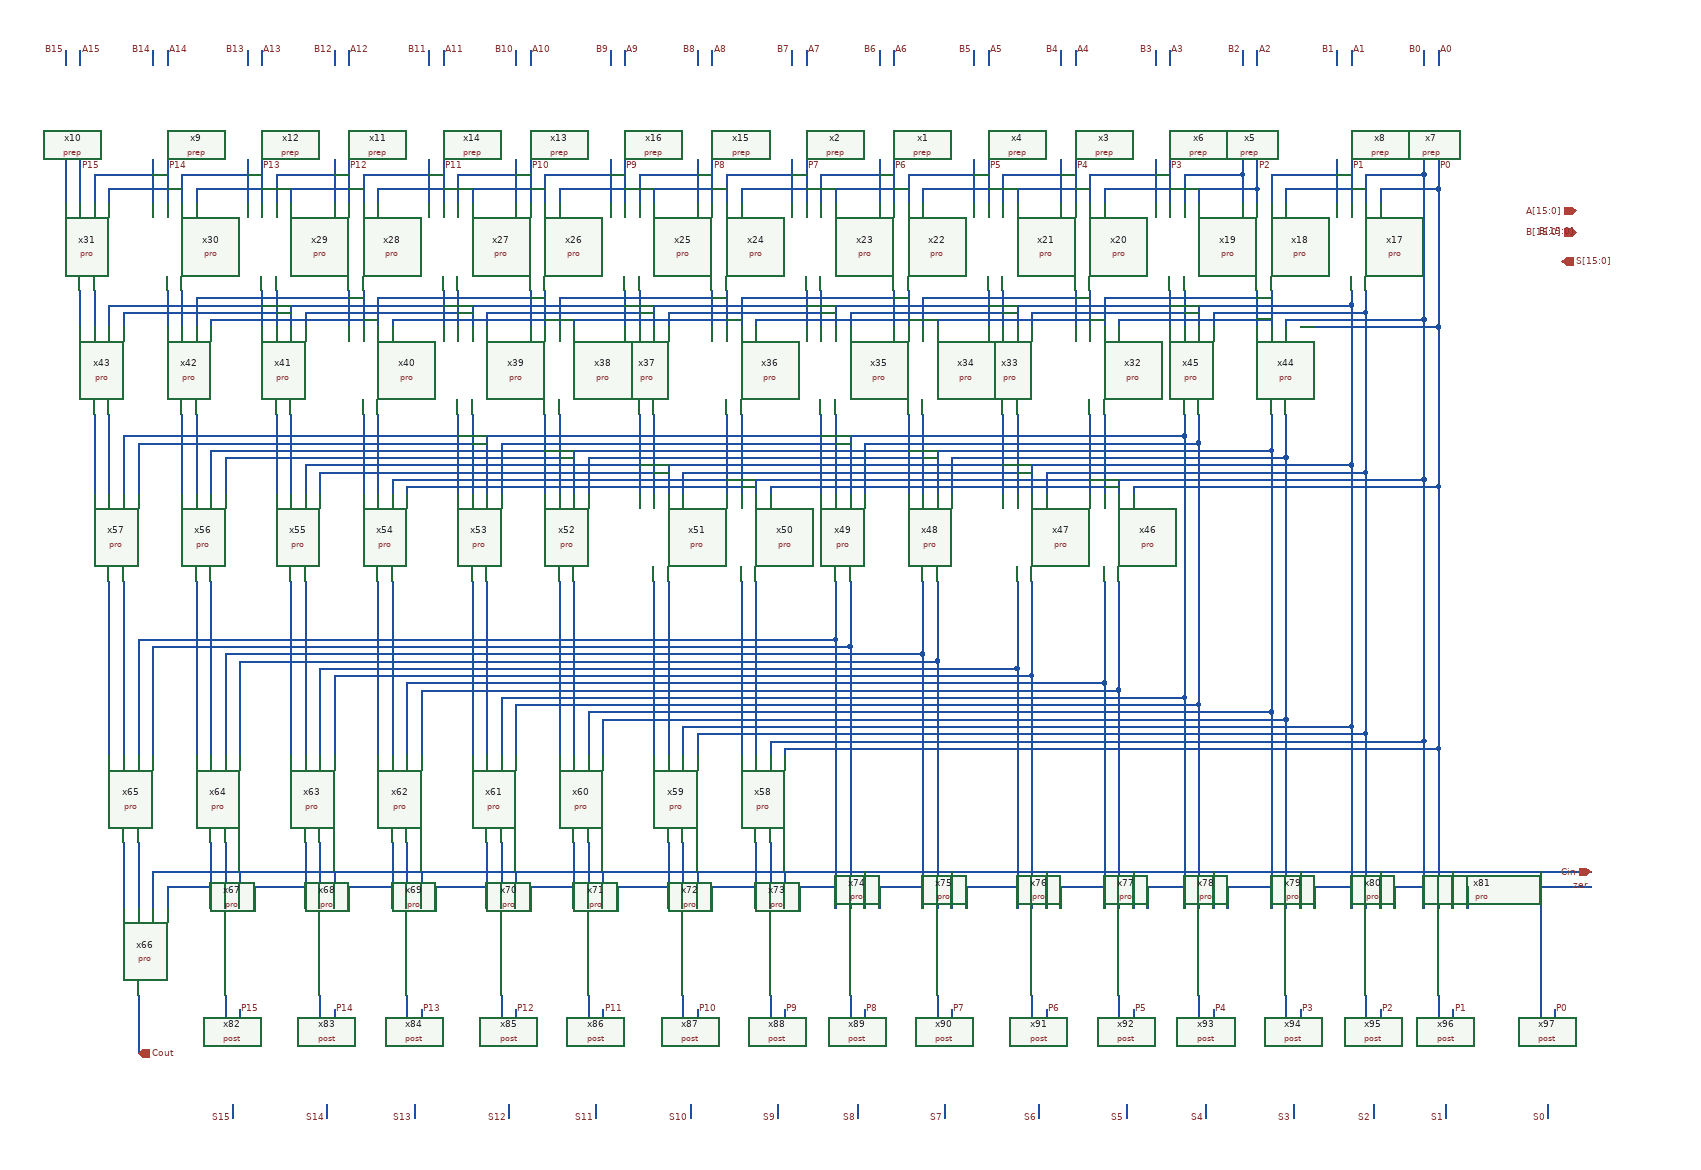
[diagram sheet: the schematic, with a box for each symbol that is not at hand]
v {xschem version=3.4.6 file_version=1.2}
G {}
K {}
V {}
S {}
E {}
N 210 -180 210 -160 {lab=A6}
N 190 -180 190 -160 {lab=B6}
N 90 -180 90 -160 {lab=A7}
N 70 -180 70 -160 {lab=B7}
N 460 -180 460 -160 {lab=A4}
N 440 -180 440 -160 {lab=B4}
N 340 -180 340 -160 {lab=A5}
N 320 -180 320 -160 {lab=B5}
N 710 -180 710 -160 {lab=A2}
N 690 -180 690 -160 {lab=B2}
N 590 -180 590 -160 {lab=A3}
N 570 -180 570 -160 {lab=B3}
N 960 -180 960 -160 {lab=A0}
N 940 -180 940 -160 {lab=B0}
N 840 -180 840 -160 {lab=A1}
N 820 -180 820 -160 {lab=B1}
N -790 -180 -790 -160 {lab=A14}
N -810 -180 -810 -160 {lab=B14}
N -910 -180 -910 -160 {lab=A15}
N -930 -180 -930 -160 {lab=B15}
N -540 -180 -540 -160 {lab=A12}
N -560 -180 -560 -160 {lab=B12}
N -660 -180 -660 -160 {lab=A13}
N -680 -180 -680 -160 {lab=B13}
N -290 -180 -290 -160 {lab=A10}
N -310 -180 -310 -160 {lab=B10}
N -410 -180 -410 -160 {lab=A11}
N -430 -180 -430 -160 {lab=B11}
N -40 -180 -40 -160 {lab=A8}
N -60 -180 -60 -160 {lab=B8}
N -160 -180 -160 -160 {lab=A9}
N -180 -180 -180 -160 {lab=B9}
N 940 -30 940 -10 {lab=#net1}
N 860 -10 940 -10 {lab=#net1}
N 860 -10 860 30 {lab=#net1}
N 880 10 880 30 {lab=P0}
N 880 10 960 10 {lab=P0}
N 960 -30 960 10 {lab=P0}
N 840 -30 840 30 {lab=P1}
N 820 -30 820 30 {lab=#net2}
N 730 -10 810 -10 {lab=#net2}
N 730 -10 730 30 {lab=#net2}
N 750 10 750 30 {lab=P1}
N 750 10 830 10 {lab=P1}
N 810 -10 820 -10 {lab=#net2}
N 830 10 840 10 {lab=P1}
N 690 -30 690 -10 {lab=#net3}
N 610 -10 690 -10 {lab=#net3}
N 610 -10 610 30 {lab=#net3}
N 630 10 630 30 {lab=P2}
N 630 10 710 10 {lab=P2}
N 710 -30 710 10 {lab=P2}
N 590 -30 590 30 {lab=P3}
N 570 -30 570 30 {lab=#net4}
N 690 -10 690 30 {lab=#net3}
N 710 10 710 30 {lab=P2}
N 480 -10 560 -10 {lab=#net4}
N 480 -10 480 30 {lab=#net4}
N 500 10 500 30 {lab=P3}
N 500 10 580 10 {lab=P3}
N 460 -30 460 30 {lab=P4}
N 440 -30 440 30 {lab=#net5}
N 580 10 590 10 {lab=P3}
N 560 -10 570 -10 {lab=#net4}
N 380 10 380 30 {lab=P4}
N 380 10 460 10 {lab=P4}
N 360 -10 440 -10 {lab=#net5}
N 360 -10 360 30 {lab=#net5}
N 340 -30 340 30 {lab=P5}
N 320 -30 320 30 {lab=#net6}
N 250 10 250 30 {lab=P5}
N 250 10 340 10 {lab=P5}
N 230 -10 320 -10 {lab=#net6}
N 230 -10 230 30 {lab=#net6}
N 210 -30 210 30 {lab=P6}
N 190 -30 190 30 {lab=#net7}
N 130 10 130 30 {lab=P6}
N 130 10 210 10 {lab=P6}
N 110 -10 190 -10 {lab=#net7}
N 110 -10 110 30 {lab=#net7}
N 90 -30 90 30 {lab=P7}
N 70 -30 70 30 {lab=#net8}
N -60 -30 -60 30 {lab=#net9}
N -40 -30 -40 30 {lab=P8}
N -20 -10 -20 30 {lab=#net8}
N -20 -10 70 -10 {lab=#net8}
N 0 10 90 10 {lab=P7}
N 0 10 0 30 {lab=P7}
N -180 -30 -180 30 {lab=#net10}
N -160 -30 -160 30 {lab=P9}
N -140 -10 -140 30 {lab=#net9}
N -140 -10 -60 -10 {lab=#net9}
N -120 10 -40 10 {lab=P8}
N -120 10 -120 30 {lab=P8}
N -310 -30 -310 30 {lab=#net11}
N -290 -30 -290 30 {lab=P10}
N -270 -10 -270 30 {lab=#net10}
N -270 -10 -180 -10 {lab=#net10}
N -250 10 -160 10 {lab=P9}
N -250 10 -250 30 {lab=P9}
N -370 10 -370 30 {lab=P10}
N -370 10 -290 10 {lab=P10}
N -390 -10 -310 -10 {lab=#net11}
N -390 -10 -390 30 {lab=#net11}
N -410 -30 -410 30 {lab=P11}
N -430 -30 -430 30 {lab=#net12}
N -540 -30 -540 30 {lab=P12}
N -560 -30 -560 30 {lab=#net13}
N -520 -10 -520 30 {lab=#net12}
N -520 -10 -430 -10 {lab=#net12}
N -500 10 -410 10 {lab=P11}
N -500 10 -500 30 {lab=P11}
N -660 -30 -660 30 {lab=P13}
N -680 -30 -680 30 {lab=#net14}
N -640 -10 -640 30 {lab=#net13}
N -640 -10 -560 -10 {lab=#net13}
N -620 10 -620 30 {lab=P12}
N -810 -30 -810 30 {lab=#net15}
N -790 -30 -790 30 {lab=P14}
N -770 -10 -770 30 {lab=#net14}
N -770 -10 -680 -10 {lab=#net14}
N -750 10 -750 30 {lab=P13}
N -930 -30 -930 30 {lab=#net16}
N -910 -30 -910 30 {lab=P15}
N -890 -10 -890 30 {lab=#net15}
N -890 -10 -810 -10 {lab=#net15}
N -870 10 -790 10 {lab=P14}
N -870 10 -870 30 {lab=P14}
N 940 -10 940 150 {lab=#net1}
N 960 10 960 180 {lab=P0}
N 770 200 960 200 {lab=P0}
N 960 180 960 200 {lab=P0}
N 750 190 750 200 {lab=#net1}
N 750 190 940 190 {lab=#net1}
N 940 150 940 190 {lab=#net1}
N 730 150 730 200 {lab=#net17}
N 710 150 710 200 {lab=#net18}
N 650 180 650 200 {lab=#net19}
N 650 180 860 180 {lab=#net19}
N 860 150 860 180 {lab=#net19}
N 840 150 840 170 {lab=#net20}
N 630 170 840 170 {lab=#net20}
N 630 170 630 200 {lab=#net20}
N 610 150 610 200 {lab=#net21}
N 590 150 590 200 {lab=#net22}
N 520 190 520 200 {lab=#net17}
N 520 190 730 190 {lab=#net17}
N 500 160 500 200 {lab=#net18}
N 480 150 480 200 {lab=#net23}
N 460 150 460 200 {lab=#net24}
N 400 180 610 180 {lab=#net21}
N 400 180 400 200 {lab=#net21}
N 500 160 710 160 {lab=#net18}
N 380 170 590 170 {lab=#net22}
N 380 170 380 200 {lab=#net22}
N 360 150 360 200 {lab=#net25}
N 340 150 340 200 {lab=#net26}
N 270 190 480 190 {lab=#net23}
N 270 190 270 200 {lab=#net23}
N 250 160 250 200 {lab=#net24}
N 250 160 460 160 {lab=#net24}
N 230 150 230 200 {lab=#net27}
N 210 150 210 200 {lab=#net28}
N 150 180 360 180 {lab=#net25}
N 150 180 150 200 {lab=#net25}
N 130 170 130 200 {lab=#net26}
N 130 170 340 170 {lab=#net26}
N 110 150 110 200 {lab=#net29}
N 90 150 90 200 {lab=#net30}
N 20 190 230 190 {lab=#net27}
N 20 190 20 200 {lab=#net27}
N 0 160 210 160 {lab=#net28}
N 0 160 0 200 {lab=#net28}
N -20 150 -20 200 {lab=#net31}
N -40 150 -40 200 {lab=#net32}
N -100 180 110 180 {lab=#net29}
N -100 180 -100 200 {lab=#net29}
N -120 170 90 170 {lab=#net30}
N -120 170 -120 200 {lab=#net30}
N -140 150 -140 200 {lab=#net33}
N -160 150 -160 200 {lab=#net34}
N -250 160 -40 160 {lab=#net32}
N -250 160 -250 200 {lab=#net32}
N -230 190 -230 200 {lab=#net31}
N -230 190 -20 190 {lab=#net31}
N -270 150 -270 200 {lab=#net35}
N -290 150 -290 200 {lab=#net36}
N -350 180 -140 180 {lab=#net33}
N -350 180 -350 200 {lab=#net33}
N -370 170 -160 170 {lab=#net34}
N -370 170 -370 200 {lab=#net34}
N -390 150 -390 200 {lab=#net37}
N -410 150 -410 200 {lab=#net38}
N -500 160 -500 200 {lab=#net36}
N -480 190 -480 200 {lab=#net35}
N -480 190 -270 190 {lab=#net35}
N -500 160 -290 160 {lab=#net36}
N -520 150 -520 200 {lab=#net39}
N -540 150 -540 200 {lab=#net40}
N -600 180 -390 180 {lab=#net37}
N -600 180 -600 200 {lab=#net37}
N -620 170 -620 200 {lab=#net38}
N -620 170 -410 170 {lab=#net38}
N -640 150 -640 200 {lab=#net41}
N -660 150 -660 200 {lab=#net42}
N -730 190 -520 190 {lab=#net39}
N -730 190 -730 200 {lab=#net39}
N -750 160 -540 160 {lab=#net40}
N -750 160 -750 200 {lab=#net40}
N -770 150 -770 200 {lab=#net43}
N -790 150 -790 200 {lab=#net44}
N -850 180 -640 180 {lab=#net41}
N -850 180 -850 200 {lab=#net41}
N -870 170 -870 200 {lab=#net42}
N -870 170 -660 170 {lab=#net42}
N -910 150 -910 200 {lab=#net45}
N -890 150 -890 200 {lab=#net46}
N 960 200 960 420 {lab=P0}
N 540 420 960 420 {lab=P0}
N 540 420 540 430 {lab=P0}
N 520 410 520 430 {lab=#net1}
N 520 410 940 410 {lab=#net1}
N 940 190 940 410 {lab=#net1}
N 860 180 860 400 {lab=#net19}
N 420 400 860 400 {lab=#net19}
N 420 400 420 430 {lab=#net19}
N 400 390 400 430 {lab=#net20}
N 400 390 840 390 {lab=#net20}
N 840 170 840 390 {lab=#net20}
N 750 320 750 380 {lab=#net47}
N 290 380 750 380 {lab=#net47}
N 290 380 290 430 {lab=#net47}
N 270 370 270 430 {lab=#net48}
N 270 370 730 370 {lab=#net48}
N 730 320 730 370 {lab=#net48}
N 630 320 630 360 {lab=#net49}
N 170 360 630 360 {lab=#net49}
N 170 360 170 430 {lab=#net49}
N 150 350 150 430 {lab=#net50}
N 150 350 610 350 {lab=#net50}
N 610 320 610 350 {lab=#net50}
N 500 320 500 430 {lab=#net51}
N 480 320 480 430 {lab=#net52}
N 40 420 500 420 {lab=#net51}
N 40 420 40 430 {lab=#net51}
N 20 410 20 430 {lab=#net52}
N 20 410 480 410 {lab=#net52}
N 380 320 380 430 {lab=#net53}
N 360 320 360 430 {lab=#net54}
N 250 320 250 430 {lab=#net55}
N 230 320 230 430 {lab=#net56}
N 130 320 130 430 {lab=#net57}
N 110 320 110 430 {lab=#net58}
N -80 400 -80 430 {lab=#net53}
N -80 400 380 400 {lab=#net53}
N -100 390 360 390 {lab=#net54}
N -100 390 -100 430 {lab=#net54}
N 0 320 -0 430 {lab=#net59}
N -20 320 -20 430 {lab=#net60}
N -120 320 -120 430 {lab=#net61}
N -140 320 -140 430 {lab=#net62}
N -210 380 250 380 {lab=#net55}
N -210 380 -210 430 {lab=#net55}
N -230 370 230 370 {lab=#net56}
N -230 370 -230 430 {lab=#net56}
N -250 320 -250 430 {lab=#net63}
N -270 320 -270 430 {lab=#net64}
N -330 360 130 360 {lab=#net57}
N -330 360 -330 430 {lab=#net57}
N -350 350 -350 430 {lab=#net58}
N -350 350 110 350 {lab=#net58}
N -370 320 -370 430 {lab=#net65}
N -390 320 -390 430 {lab=#net66}
N -460 420 -460 430 {lab=#net59}
N -460 420 0 420 {lab=#net59}
N -480 410 -20 410 {lab=#net60}
N -480 410 -480 430 {lab=#net60}
N -500 320 -500 430 {lab=#net67}
N -520 320 -520 430 {lab=#net68}
N -580 400 -120 400 {lab=#net61}
N -580 400 -580 430 {lab=#net61}
N -600 390 -600 430 {lab=#net62}
N -600 390 -140 390 {lab=#net62}
N -710 380 -250 380 {lab=#net63}
N -710 380 -710 430 {lab=#net63}
N -730 370 -730 430 {lab=#net64}
N -730 370 -270 370 {lab=#net64}
N -620 320 -620 430 {lab=#net69}
N -640 320 -640 430 {lab=#net70}
N -750 320 -750 430 {lab=#net71}
N -770 320 -770 430 {lab=#net72}
N -830 360 -370 360 {lab=#net65}
N -830 360 -830 430 {lab=#net65}
N -850 350 -850 430 {lab=#net66}
N -850 350 -390 350 {lab=#net66}
N -870 320 -870 430 {lab=#net73}
N -890 320 -890 430 {lab=#net74}
N 960 420 960 780 {lab=P0}
N 60 780 960 780 {lab=P0}
N 60 780 60 790 {lab=P0}
N 940 410 940 760 {lab=#net1}
N 860 400 860 740 {lab=#net19}
N 40 770 40 790 {lab=#net1}
N 40 770 940 770 {lab=#net1}
N 940 760 940 770 {lab=#net1}
N 860 740 860 760 {lab=#net19}
N -60 760 860 760 {lab=#net19}
N -60 760 -60 790 {lab=#net19}
N -80 750 -80 790 {lab=#net20}
N -80 750 840 750 {lab=#net20}
N 840 390 840 750 {lab=#net20}
N 750 380 750 740 {lab=#net47}
N -180 740 750 740 {lab=#net47}
N 730 370 730 730 {lab=#net48}
N -200 730 730 730 {lab=#net48}
N 20 550 20 790 {lab=#net75}
N -0 550 -0 790 {lab=#net76}
N -100 550 -100 790 {lab=#net77}
N -120 550 -120 790 {lab=#net78}
N -190 740 -190 790 {lab=#net47}
N -190 740 -180 740 {lab=#net47}
N -210 730 -200 730 {lab=#net48}
N -210 730 -210 790 {lab=#net48}
N -230 550 -230 790 {lab=#net79}
N -250 550 -250 790 {lab=#net80}
N 630 360 630 720 {lab=#net49}
N -310 720 630 720 {lab=#net49}
N -310 720 -310 790 {lab=#net49}
N -330 710 -330 790 {lab=#net50}
N 610 350 610 710 {lab=#net50}
N -330 710 610 710 {lab=#net50}
N -350 550 -350 790 {lab=#net81}
N -370 550 -370 790 {lab=#net82}
N 520 550 520 700 {lab=#net83}
N -430 700 520 700 {lab=#net83}
N -450 690 500 690 {lab=#net84}
N 500 550 500 690 {lab=#net84}
N 400 550 400 680 {lab=#net85}
N -560 680 400 680 {lab=#net85}
N -560 680 -560 790 {lab=#net85}
N 380 550 380 670 {lab=#net86}
N -580 670 380 670 {lab=#net86}
N -580 670 -580 790 {lab=#net86}
N -620 550 -620 790 {lab=#net87}
N -600 550 -600 790 {lab=#net88}
N -870 550 -870 790 {lab=#net89}
N -850 550 -850 790 {lab=#net90}
N -750 550 -750 790 {lab=#net91}
N -730 550 -730 790 {lab=#net92}
N -460 690 -460 790 {lab=#net84}
N -460 690 -450 690 {lab=#net84}
N -440 700 -430 700 {lab=#net83}
N -440 700 -440 790 {lab=#net83}
N -480 550 -480 790 {lab=#net93}
N -500 550 -500 790 {lab=#net94}
N 270 550 270 660 {lab=#net95}
N -690 660 270 660 {lab=#net95}
N -690 660 -690 790 {lab=#net95}
N -710 650 -710 790 {lab=#net96}
N -710 650 250 650 {lab=#net96}
N 250 550 250 650 {lab=#net96}
N 150 550 150 640 {lab=#net97}
N -810 640 150 640 {lab=#net97}
N -810 640 -810 790 {lab=#net97}
N -830 630 -830 790 {lab=#net98}
N -830 630 130 630 {lab=#net98}
N 130 550 130 630 {lab=#net98}
N -810 950 -810 1000 {lab=Cin}
N -790 970 -790 1000 {lab=zer}
N -830 1120 -830 1200 {lab=Cout}
N -710 1120 -710 1150 {lab=#net99}
N -580 1120 -580 1150 {lab=#net100}
N -460 1120 -460 1150 {lab=#net101}
N -330 1120 -330 1150 {lab=#net102}
N -210 1120 -210 1150 {lab=#net103}
N -80 1120 -80 1150 {lab=#net104}
N 40 1120 40 1150 {lab=#net105}
N 150 1120 150 1150 {lab=#net106}
N 270 1120 270 1150 {lab=#net107}
N 400 1120 400 1150 {lab=#net108}
N 520 1120 520 1150 {lab=#net109}
N 630 1120 630 1150 {lab=#net110}
N 750 1120 750 1150 {lab=#net111}
N 860 1120 860 1150 {lab=#net112}
N 960 1120 960 1150 {lab=#net113}
N 1100 950 1100 1150 {lab=Cin}
N 1120 1140 1120 1150 {lab=P0}
N 980 1140 980 1150 {lab=P1}
N 880 1140 880 1150 {lab=P2}
N 770 1140 770 1150 {lab=P3}
N 650 1140 650 1150 {lab=P4}
N 540 1140 540 1150 {lab=P5}
N 420 1140 420 1150 {lab=P6}
N 290 1140 290 1150 {lab=P7}
N 170 1140 170 1150 {lab=P8}
N 60 1140 60 1150 {lab=P9}
N -60 1140 -60 1150 {lab=P10}
N -190 1140 -190 1150 {lab=P11}
N -310 1140 -310 1150 {lab=P12}
N -440 1140 -440 1150 {lab=P13}
N -560 1140 -560 1150 {lab=P14}
N -690 1140 -690 1150 {lab=P15}
N 1110 1270 1110 1290 {lab=S0}
N 970 1270 970 1290 {lab=S1}
N 870 1270 870 1290 {lab=S2}
N 760 1270 760 1290 {lab=S3}
N 640 1270 640 1290 {lab=S4}
N 530 1270 530 1290 {lab=S5}
N 410 1270 410 1290 {lab=S6}
N 280 1270 280 1290 {lab=S7}
N 160 1270 160 1290 {lab=S8}
N 50 1270 50 1290 {lab=S9}
N -70 1270 -70 1290 {lab=S10}
N -200 1270 -200 1290 {lab=S11}
N -320 1270 -320 1290 {lab=S12}
N -450 1270 -450 1290 {lab=S13}
N -570 1270 -570 1290 {lab=S14}
N -700 1270 -700 1290 {lab=S15}
N -850 910 -850 1000 {lab=#net114}
N -830 910 -830 1000 {lab=#net115}
N -670 970 -670 1000 {lab=zer}
N -690 950 -690 1000 {lab=Cin}
N -710 910 -710 1000 {lab=#net116}
N -730 910 -730 1000 {lab=#net117}
N -600 910 -600 1000 {lab=#net118}
N -580 910 -580 1000 {lab=#net119}
N -560 950 -560 1000 {lab=Cin}
N -540 970 -540 1000 {lab=zer}
N -480 910 -480 1000 {lab=#net120}
N -460 910 -460 1000 {lab=#net121}
N -440 950 -440 1000 {lab=Cin}
N -420 970 -420 1000 {lab=zer}
N -350 910 -350 1000 {lab=#net122}
N -330 910 -330 1000 {lab=#net123}
N -310 950 -310 1000 {lab=Cin}
N -290 970 -290 1000 {lab=zer}
N -230 910 -230 1000 {lab=#net124}
N -210 910 -210 1000 {lab=#net125}
N -190 950 -190 1000 {lab=Cin}
N -170 970 -170 1000 {lab=zer}
N -100 910 -100 1000 {lab=#net126}
N -80 910 -80 1000 {lab=#net127}
N -60 950 -60 1000 {lab=Cin}
N -40 970 -40 1000 {lab=zer}
N 20 910 20 1000 {lab=#net128}
N 40 910 40 1000 {lab=#net129}
N 60 950 60 1000 {lab=Cin}
N 80 970 80 1000 {lab=zer}
N 130 630 130 1000 {lab=#net98}
N 150 640 150 1000 {lab=#net97}
N 170 950 170 1000 {lab=Cin}
N 250 650 250 1000 {lab=#net96}
N 270 660 270 1000 {lab=#net95}
N 290 950 290 1000 {lab=Cin}
N 310 970 310 1000 {lab=zer}
N 190 970 190 1000 {lab=zer}
N 380 670 380 1000 {lab=#net86}
N 400 680 400 1000 {lab=#net85}
N 420 950 420 1000 {lab=Cin}
N 440 970 440 1000 {lab=zer}
N 500 690 500 1000 {lab=#net84}
N 520 700 520 1000 {lab=#net83}
N 540 950 540 1000 {lab=Cin}
N 560 970 560 1000 {lab=zer}
N 610 710 610 1000 {lab=#net50}
N 630 720 630 1000 {lab=#net49}
N 650 950 650 1000 {lab=Cin}
N 670 970 670 1000 {lab=zer}
N 730 730 730 1000 {lab=#net48}
N 750 740 750 1000 {lab=#net47}
N 770 950 770 1000 {lab=Cin}
N 790 970 790 1000 {lab=zer}
N 840 750 840 1000 {lab=#net20}
N 860 760 860 1000 {lab=#net19}
N 880 950 880 1000 {lab=Cin}
N 900 970 900 1000 {lab=zer}
N 940 770 940 1000 {lab=#net1}
N 960 780 960 1000 {lab=P0}
N 980 950 980 1000 {lab=Cin}
N 1000 970 1000 1000 {lab=zer}
N -750 10 -660 10 {lab=P13}
N -620 10 -540 10 {lab=P12}
N -810 950 1170 950 {lab=Cin}
N -790 970 1170 970 {lab=zer}
C {/home/EE23B038/ee5311/tutorial_9/prep.sym} 190 -80 0 0 {name=x1}
C {lab_pin.sym} 210 -180 2 0 {name=p1 verilog_type=logic lab=A6}
C {lab_pin.sym} 190 -180 0 0 {name=p2 verilog_type=logic lab=B6}
C {noconn.sym} 190 -160 0 0 {name=l1}
C {noconn.sym} 210 -160 2 0 {name=l2}
C {/home/EE23B038/ee5311/tutorial_9/prep.sym} 70 -80 0 0 {name=x2}
C {lab_pin.sym} 90 -180 2 0 {name=p3 verilog_type=logic lab=A7}
C {lab_pin.sym} 70 -180 0 0 {name=p4 verilog_type=logic lab=B7}
C {noconn.sym} 70 -160 0 0 {name=l3}
C {noconn.sym} 90 -160 2 0 {name=l4}
C {/home/EE23B038/ee5311/tutorial_9/prep.sym} 440 -80 0 0 {name=x3}
C {lab_pin.sym} 460 -180 2 0 {name=p5 verilog_type=logic lab=A4}
C {lab_pin.sym} 440 -180 0 0 {name=p6 verilog_type=logic lab=B4}
C {noconn.sym} 440 -160 0 0 {name=l5}
C {noconn.sym} 460 -160 2 0 {name=l6}
C {/home/EE23B038/ee5311/tutorial_9/prep.sym} 320 -80 0 0 {name=x4}
C {lab_pin.sym} 340 -180 2 0 {name=p7 verilog_type=logic lab=A5}
C {lab_pin.sym} 320 -180 0 0 {name=p8 verilog_type=logic lab=B5}
C {noconn.sym} 320 -160 0 0 {name=l7}
C {noconn.sym} 340 -160 2 0 {name=l8}
C {/home/EE23B038/ee5311/tutorial_9/prep.sym} 690 -80 0 0 {name=x5}
C {lab_pin.sym} 710 -180 2 0 {name=p9 verilog_type=logic lab=A2}
C {lab_pin.sym} 690 -180 0 0 {name=p10 verilog_type=logic lab=B2}
C {noconn.sym} 690 -160 0 0 {name=l9}
C {noconn.sym} 710 -160 2 0 {name=l10}
C {/home/EE23B038/ee5311/tutorial_9/prep.sym} 570 -80 0 0 {name=x6}
C {lab_pin.sym} 590 -180 2 0 {name=p11 verilog_type=logic lab=A3}
C {lab_pin.sym} 570 -180 0 0 {name=p12 verilog_type=logic lab=B3}
C {noconn.sym} 570 -160 0 0 {name=l11}
C {noconn.sym} 590 -160 2 0 {name=l12}
C {/home/EE23B038/ee5311/tutorial_9/prep.sym} 940 -80 0 0 {name=x7}
C {lab_pin.sym} 960 -180 2 0 {name=p13 verilog_type=logic lab=A0}
C {lab_pin.sym} 940 -180 0 0 {name=p14 verilog_type=logic lab=B0}
C {noconn.sym} 940 -160 0 0 {name=l13}
C {noconn.sym} 960 -160 2 0 {name=l14}
C {/home/EE23B038/ee5311/tutorial_9/prep.sym} 820 -80 0 0 {name=x8}
C {lab_pin.sym} 840 -180 2 0 {name=p15 verilog_type=logic lab=A1}
C {lab_pin.sym} 820 -180 0 0 {name=p16 verilog_type=logic lab=B1}
C {noconn.sym} 820 -160 0 0 {name=l15}
C {noconn.sym} 840 -160 2 0 {name=l16}
C {/home/EE23B038/ee5311/tutorial_9/prep.sym} -810 -80 0 0 {name=x9}
C {lab_pin.sym} -790 -180 2 0 {name=p17 verilog_type=logic lab=A14}
C {lab_pin.sym} -810 -180 0 0 {name=p18 verilog_type=logic lab=B14}
C {noconn.sym} -810 -160 0 0 {name=l17}
C {noconn.sym} -790 -160 2 0 {name=l18}
C {/home/EE23B038/ee5311/tutorial_9/prep.sym} -930 -80 0 0 {name=x10}
C {lab_pin.sym} -910 -180 2 0 {name=p19 verilog_type=logic lab=A15}
C {lab_pin.sym} -930 -180 0 0 {name=p20 verilog_type=logic lab=B15}
C {noconn.sym} -930 -160 0 0 {name=l19}
C {noconn.sym} -910 -160 2 0 {name=l20}
C {/home/EE23B038/ee5311/tutorial_9/prep.sym} -560 -80 0 0 {name=x11}
C {lab_pin.sym} -540 -180 2 0 {name=p21 verilog_type=logic lab=A12}
C {lab_pin.sym} -560 -180 0 0 {name=p22 verilog_type=logic lab=B12}
C {noconn.sym} -560 -160 0 0 {name=l21}
C {noconn.sym} -540 -160 2 0 {name=l22}
C {/home/EE23B038/ee5311/tutorial_9/prep.sym} -680 -80 0 0 {name=x12}
C {lab_pin.sym} -660 -180 2 0 {name=p23 verilog_type=logic lab=A13}
C {lab_pin.sym} -680 -180 0 0 {name=p24 verilog_type=logic lab=B13}
C {noconn.sym} -680 -160 0 0 {name=l23}
C {noconn.sym} -660 -160 2 0 {name=l24}
C {/home/EE23B038/ee5311/tutorial_9/prep.sym} -310 -80 0 0 {name=x13}
C {lab_pin.sym} -290 -180 2 0 {name=p25 verilog_type=logic lab=A10}
C {lab_pin.sym} -310 -180 0 0 {name=p26 verilog_type=logic lab=B10}
C {noconn.sym} -310 -160 0 0 {name=l25}
C {noconn.sym} -290 -160 2 0 {name=l26}
C {/home/EE23B038/ee5311/tutorial_9/prep.sym} -430 -80 0 0 {name=x14}
C {lab_pin.sym} -410 -180 2 0 {name=p27 verilog_type=logic lab=A11}
C {lab_pin.sym} -430 -180 0 0 {name=p28 verilog_type=logic lab=B11}
C {noconn.sym} -430 -160 0 0 {name=l27}
C {noconn.sym} -410 -160 2 0 {name=l28}
C {/home/EE23B038/ee5311/tutorial_9/prep.sym} -60 -80 0 0 {name=x15}
C {lab_pin.sym} -40 -180 2 0 {name=p29 verilog_type=logic lab=A8}
C {lab_pin.sym} -60 -180 0 0 {name=p30 verilog_type=logic lab=B8}
C {noconn.sym} -60 -160 0 0 {name=l29}
C {noconn.sym} -40 -160 2 0 {name=l30}
C {/home/EE23B038/ee5311/tutorial_9/prep.sym} -180 -80 0 0 {name=x16}
C {lab_pin.sym} -160 -180 2 0 {name=p31 verilog_type=logic lab=A9}
C {lab_pin.sym} -180 -180 0 0 {name=p32 verilog_type=logic lab=B9}
C {noconn.sym} -180 -160 0 0 {name=l31}
C {noconn.sym} -160 -160 2 0 {name=l32}
C {/home/EE23B038/ee5311/tutorial_9/pro.sym} 830 100 0 0 {name=x17}
C {/home/EE23B038/ee5311/tutorial_9/pro.sym} 700 100 0 0 {name=x18}
C {/home/EE23B038/ee5311/tutorial_9/pro.sym} 580 100 0 0 {name=x19}
C {/home/EE23B038/ee5311/tutorial_9/pro.sym} 450 100 0 0 {name=x20}
C {/home/EE23B038/ee5311/tutorial_9/pro.sym} 330 100 0 0 {name=x21}
C {/home/EE23B038/ee5311/tutorial_9/pro.sym} 200 100 0 0 {name=x22}
C {/home/EE23B038/ee5311/tutorial_9/pro.sym} 80 100 0 0 {name=x23}
C {/home/EE23B038/ee5311/tutorial_9/pro.sym} -50 100 0 0 {name=x24}
C {/home/EE23B038/ee5311/tutorial_9/pro.sym} -170 100 0 0 {name=x25}
C {/home/EE23B038/ee5311/tutorial_9/pro.sym} -300 100 0 0 {name=x26}
C {/home/EE23B038/ee5311/tutorial_9/pro.sym} -420 100 0 0 {name=x27}
C {/home/EE23B038/ee5311/tutorial_9/pro.sym} -550 100 0 0 {name=x28}
C {/home/EE23B038/ee5311/tutorial_9/pro.sym} -670 100 0 0 {name=x29}
C {/home/EE23B038/ee5311/tutorial_9/pro.sym} -800 100 0 0 {name=x30}
C {/home/EE23B038/ee5311/tutorial_9/pro.sym} -920 100 0 0 {name=x31}
C {/home/EE23B038/ee5311/tutorial_9/pro.sym} 470 270 0 0 {name=x32}
C {/home/EE23B038/ee5311/tutorial_9/pro.sym} 350 270 0 0 {name=x33}
C {/home/EE23B038/ee5311/tutorial_9/pro.sym} 220 270 0 0 {name=x34}
C {/home/EE23B038/ee5311/tutorial_9/pro.sym} 100 270 0 0 {name=x35}
C {/home/EE23B038/ee5311/tutorial_9/pro.sym} -30 270 0 0 {name=x36}
C {/home/EE23B038/ee5311/tutorial_9/pro.sym} -150 270 0 0 {name=x37}
C {/home/EE23B038/ee5311/tutorial_9/pro.sym} -280 270 0 0 {name=x38}
C {/home/EE23B038/ee5311/tutorial_9/pro.sym} -400 270 0 0 {name=x39}
C {/home/EE23B038/ee5311/tutorial_9/pro.sym} -530 270 0 0 {name=x40}
C {/home/EE23B038/ee5311/tutorial_9/pro.sym} -650 270 0 0 {name=x41}
C {/home/EE23B038/ee5311/tutorial_9/pro.sym} -780 270 0 0 {name=x42}
C {/home/EE23B038/ee5311/tutorial_9/pro.sym} -900 270 0 0 {name=x43}
C {/home/EE23B038/ee5311/tutorial_9/pro.sym} 720 270 0 0 {name=x44}
C {/home/EE23B038/ee5311/tutorial_9/pro.sym} 600 270 0 0 {name=x45}
C {/home/EE23B038/ee5311/tutorial_9/pro.sym} 490 500 0 0 {name=x46}
C {/home/EE23B038/ee5311/tutorial_9/pro.sym} 370 500 0 0 {name=x47}
C {/home/EE23B038/ee5311/tutorial_9/pro.sym} 240 500 0 0 {name=x48}
C {/home/EE23B038/ee5311/tutorial_9/pro.sym} 120 500 0 0 {name=x49}
C {/home/EE23B038/ee5311/tutorial_9/pro.sym} -10 500 0 0 {name=x50}
C {/home/EE23B038/ee5311/tutorial_9/pro.sym} -130 500 0 0 {name=x51}
C {/home/EE23B038/ee5311/tutorial_9/pro.sym} -260 500 0 0 {name=x52}
C {/home/EE23B038/ee5311/tutorial_9/pro.sym} -380 500 0 0 {name=x53}
C {/home/EE23B038/ee5311/tutorial_9/pro.sym} -510 500 0 0 {name=x54}
C {/home/EE23B038/ee5311/tutorial_9/pro.sym} -630 500 0 0 {name=x55}
C {/home/EE23B038/ee5311/tutorial_9/pro.sym} -760 500 0 0 {name=x56}
C {/home/EE23B038/ee5311/tutorial_9/pro.sym} -880 500 0 0 {name=x57}
C {/home/EE23B038/ee5311/tutorial_9/pro.sym} 10 860 0 0 {name=x58}
C {/home/EE23B038/ee5311/tutorial_9/pro.sym} -110 860 0 0 {name=x59}
C {/home/EE23B038/ee5311/tutorial_9/pro.sym} -240 860 0 0 {name=x60}
C {/home/EE23B038/ee5311/tutorial_9/pro.sym} -360 860 0 0 {name=x61}
C {/home/EE23B038/ee5311/tutorial_9/pro.sym} -490 860 0 0 {name=x62}
C {/home/EE23B038/ee5311/tutorial_9/pro.sym} -610 860 0 0 {name=x63}
C {/home/EE23B038/ee5311/tutorial_9/pro.sym} -740 860 0 0 {name=x64}
C {/home/EE23B038/ee5311/tutorial_9/pro.sym} -860 860 0 0 {name=x65}
C {/home/EE23B038/ee5311/tutorial_9/pro.sym} -840 1070 0 0 {name=x66}
C {/home/EE23B038/ee5311/tutorial_9/pro.sym} -720 1070 0 0 {name=x67}
C {/home/EE23B038/ee5311/tutorial_9/pro.sym} -590 1070 0 0 {name=x68}
C {/home/EE23B038/ee5311/tutorial_9/pro.sym} -470 1070 0 0 {name=x69}
C {/home/EE23B038/ee5311/tutorial_9/pro.sym} -340 1070 0 0 {name=x70}
C {/home/EE23B038/ee5311/tutorial_9/pro.sym} -220 1070 0 0 {name=x71}
C {/home/EE23B038/ee5311/tutorial_9/pro.sym} -90 1070 0 0 {name=x72}
C {/home/EE23B038/ee5311/tutorial_9/pro.sym} 30 1070 0 0 {name=x73}
C {/home/EE23B038/ee5311/tutorial_9/pro.sym} 140 1070 0 0 {name=x74}
C {/home/EE23B038/ee5311/tutorial_9/pro.sym} 260 1070 0 0 {name=x75}
C {/home/EE23B038/ee5311/tutorial_9/pro.sym} 390 1070 0 0 {name=x76}
C {/home/EE23B038/ee5311/tutorial_9/pro.sym} 510 1070 0 0 {name=x77}
C {/home/EE23B038/ee5311/tutorial_9/pro.sym} 620 1070 0 0 {name=x78}
C {/home/EE23B038/ee5311/tutorial_9/pro.sym} 740 1070 0 0 {name=x79}
C {/home/EE23B038/ee5311/tutorial_9/pro.sym} 850 1070 0 0 {name=x80}
C {/home/EE23B038/ee5311/tutorial_9/pro.sym} 950 1070 0 0 {name=x81}
C {ipin.sym} 1170 950 1 0 {name=p33 lab=Cin verilog_type=logic}
C {lab_pin.sym} 1170 970 3 0 {name=p34 verilog_type=logic lab=zer}
C {opin.sym} -830 1200 1 0 {name=p35 lab=Cout}
C {noconn.sym} -830 1200 0 0 {name=l33}
C {noconn.sym} 1170 950 0 0 {name=l34}
C {/home/EE23B038/ee5311/tutorial_9/post.sym} -700 1220 0 0 {name=x82}
C {/home/EE23B038/ee5311/tutorial_9/post.sym} -570 1220 0 0 {name=x83}
C {/home/EE23B038/ee5311/tutorial_9/post.sym} -450 1220 0 0 {name=x84}
C {/home/EE23B038/ee5311/tutorial_9/post.sym} -320 1220 0 0 {name=x85}
C {/home/EE23B038/ee5311/tutorial_9/post.sym} -200 1220 0 0 {name=x86}
C {/home/EE23B038/ee5311/tutorial_9/post.sym} -70 1220 0 0 {name=x87}
C {/home/EE23B038/ee5311/tutorial_9/post.sym} 50 1220 0 0 {name=x88}
C {/home/EE23B038/ee5311/tutorial_9/post.sym} 160 1220 0 0 {name=x89}
C {/home/EE23B038/ee5311/tutorial_9/post.sym} 280 1220 0 0 {name=x90}
C {/home/EE23B038/ee5311/tutorial_9/post.sym} 410 1220 0 0 {name=x91}
C {/home/EE23B038/ee5311/tutorial_9/post.sym} 530 1220 0 0 {name=x92}
C {/home/EE23B038/ee5311/tutorial_9/post.sym} 640 1220 0 0 {name=x93}
C {/home/EE23B038/ee5311/tutorial_9/post.sym} 760 1220 0 0 {name=x94}
C {/home/EE23B038/ee5311/tutorial_9/post.sym} 870 1220 0 0 {name=x95}
C {/home/EE23B038/ee5311/tutorial_9/post.sym} 970 1220 0 0 {name=x96}
C {lab_pin.sym} -310 1140 2 0 {name=p55 verilog_type=logic lab=P12}
C {lab_pin.sym} -440 1140 2 0 {name=p56 verilog_type=logic lab=P13}
C {lab_pin.sym} -560 1140 2 0 {name=p57 verilog_type=logic lab=P14}
C {lab_pin.sym} -690 1140 2 0 {name=p58 verilog_type=logic lab=P15}
C {lab_pin.sym} 170 1140 2 0 {name=p59 verilog_type=logic lab=P8}
C {lab_pin.sym} 60 1140 2 0 {name=p60 verilog_type=logic lab=P9}
C {lab_pin.sym} -60 1140 2 0 {name=p61 verilog_type=logic lab=P10}
C {lab_pin.sym} -190 1140 2 0 {name=p62 verilog_type=logic lab=P11}
C {lab_pin.sym} 880 1140 2 0 {name=p63 verilog_type=logic lab=P2}
C {lab_pin.sym} 770 1140 2 0 {name=p64 verilog_type=logic lab=P3}
C {lab_pin.sym} 650 1140 2 0 {name=p65 verilog_type=logic lab=P4}
C {lab_pin.sym} 540 1140 2 0 {name=p66 verilog_type=logic lab=P5}
C {lab_pin.sym} 420 1140 2 0 {name=p67 verilog_type=logic lab=P6}
C {lab_pin.sym} 290 1140 2 0 {name=p68 verilog_type=logic lab=P7}
C {lab_pin.sym} 1120 1140 2 0 {name=p69 verilog_type=logic lab=P0}
C {lab_pin.sym} 980 1140 2 0 {name=p70 verilog_type=logic lab=P1}
C {/home/EE23B038/ee5311/tutorial_9/post.sym} 1110 1220 0 0 {name=x97}
C {lab_pin.sym} 1110 1290 0 0 {name=p71 verilog_type=logic lab=S0}
C {lab_pin.sym} 970 1290 0 0 {name=p72 verilog_type=logic lab=S1}
C {lab_pin.sym} 870 1290 0 0 {name=p73 verilog_type=logic lab=S2}
C {lab_pin.sym} 760 1290 0 0 {name=p74 verilog_type=logic lab=S3}
C {lab_pin.sym} 640 1290 0 0 {name=p75 verilog_type=logic lab=S4}
C {lab_pin.sym} 530 1290 0 0 {name=p76 verilog_type=logic lab=S5}
C {lab_pin.sym} 410 1290 0 0 {name=p77 verilog_type=logic lab=S6}
C {lab_pin.sym} 280 1290 0 0 {name=p78 verilog_type=logic lab=S7}
C {lab_pin.sym} 160 1290 0 0 {name=p79 verilog_type=logic lab=S8}
C {lab_pin.sym} 50 1290 0 0 {name=p80 verilog_type=logic lab=S9}
C {lab_pin.sym} -70 1290 0 0 {name=p81 verilog_type=logic lab=S10}
C {lab_pin.sym} -200 1290 0 0 {name=p82 verilog_type=logic lab=S11}
C {lab_pin.sym} -320 1290 0 0 {name=p83 verilog_type=logic lab=S12}
C {lab_pin.sym} -450 1290 0 0 {name=p84 verilog_type=logic lab=S13}
C {lab_pin.sym} -570 1290 0 0 {name=p85 verilog_type=logic lab=S14}
C {lab_pin.sym} -700 1290 0 0 {name=p86 verilog_type=logic lab=S15}
C {noconn.sym} -700 1270 0 0 {name=l38}
C {noconn.sym} -570 1270 0 0 {name=l39}
C {noconn.sym} -450 1270 0 0 {name=l40}
C {noconn.sym} -320 1270 0 0 {name=l41}
C {noconn.sym} -200 1270 0 0 {name=l42}
C {noconn.sym} -70 1270 0 0 {name=l43}
C {noconn.sym} 50 1270 0 0 {name=l44}
C {noconn.sym} 160 1270 0 0 {name=l45}
C {noconn.sym} 280 1270 0 0 {name=l46}
C {noconn.sym} 410 1270 0 0 {name=l47}
C {noconn.sym} 530 1270 0 0 {name=l48}
C {noconn.sym} 640 1270 0 0 {name=l49}
C {noconn.sym} 760 1270 0 0 {name=l50}
C {noconn.sym} 870 1270 0 0 {name=l51}
C {noconn.sym} 970 1270 0 0 {name=l52}
C {noconn.sym} 1110 1270 0 0 {name=l53}
C {noconn.sym} 1170 970 0 0 {name=l54}
C {ipin.sym} 1150 40 0 0 {name=p36 lab=A[15:0] verilog_type=logic}
C {noconn.sym} 1150 40 1 0 {name=l35}
C {ipin.sym} 1150 70 0 0 {name=p37 lab=B[15:0] verilog_type=logic}
C {noconn.sym} 1150 70 1 0 {name=l36
lab=B[15:0]}
C {opin.sym} 1130 110 0 0 {name=p38 lab=S[15:0] verilog_type=logic}
C {noconn.sym} 1130 110 1 0 {name=l37}
C {verilog_code.sym} 1050 180 0 0 {name=s1 string="assign \{A15,A14,A13,A12,A11,A10,A9,A8,A7,A6,A5,A4,A3,A2,A1,A0\} = A[15:0];
assign \{B15,B14,B13,B12,B11,B10,B9,B8,B7,B6,B5,B4,B3,B2,B1,B0\} = B[15:0];
assign S[15:0] = \{S15,S14,S13,S12,S11,S10,S9,S8,S7,S6,S5,S4,S3,S2,S1,S0\};
assign zer = 0;"}
C {lab_pin.sym} 960 -20 2 0 {name=p39 verilog_type=logic lab=P0}
C {lab_pin.sym} 840 -20 2 0 {name=p40 verilog_type=logic lab=P1}
C {lab_pin.sym} 710 -20 2 0 {name=p41 verilog_type=logic lab=P2}
C {lab_pin.sym} 590 -20 2 0 {name=p42 verilog_type=logic lab=P3}
C {lab_pin.sym} 460 -20 2 0 {name=p43 verilog_type=logic lab=P4}
C {lab_pin.sym} 340 -20 2 0 {name=p44 verilog_type=logic lab=P5}
C {lab_pin.sym} 210 -20 2 0 {name=p45 verilog_type=logic lab=P6}
C {lab_pin.sym} -40 -20 2 0 {name=p46 verilog_type=logic lab=P8
}
C {lab_pin.sym} 90 -20 2 0 {name=p47 verilog_type=logic lab=P7}
C {lab_pin.sym} -160 -20 2 0 {name=p48 verilog_type=logic lab=P9}
C {lab_pin.sym} -290 -20 2 0 {name=p49 verilog_type=logic lab=P10}
C {lab_pin.sym} -410 -20 2 0 {name=p50 verilog_type=logic lab=P11}
C {lab_pin.sym} -540 -20 2 0 {name=p51 verilog_type=logic lab=P12}
C {lab_pin.sym} -660 -20 2 0 {name=p52 verilog_type=logic lab=P13}
C {lab_pin.sym} -790 -20 2 0 {name=p53 verilog_type=logic lab=P14}
C {lab_pin.sym} -910 -20 2 0 {name=p54 verilog_type=logic lab=P15}
